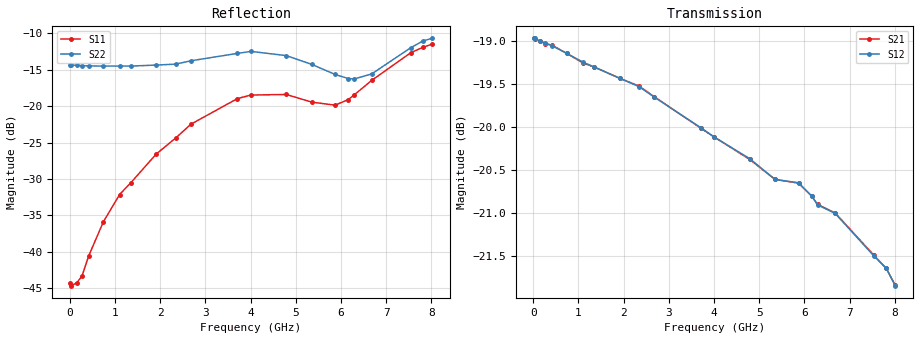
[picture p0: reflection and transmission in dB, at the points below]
! DEVICE ID: PE43712
! File Path: z:\PE43713\PE43713_CHAR_NOM_04292014\AMB\3p300\LS_ATT_17p75dB\PE43713_AMB_3p300V_3p000V_0p000V_LS_ATT_17p75dB_S2P_SN_10_A0139A.s2p
! Serial: 10
! Lot: A0139A
! Temp: 25C
! VDD: 3.300
! VSS: 0.000
! Control_Hi: 3.000
! Control_Lo: 0.000
! Attenuation Step: 17.75dB
! Port 1: RF1
! Port 2: RF2
! ThroughPath:1-2
! IDD: 0.0001466372
! ISS: -8.97e-008
#  Hz  S  RI  R  50
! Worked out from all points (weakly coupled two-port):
!   801 points, 10 MHz to 8.01 GHz, reference 50 ohm
!   highest |S21| = -18.97 dB at 10 MHz (marker M1); lowest = -21.8 dB at 8.01 GHz (marker M2)
!   lowest |S11| = -44.7 dB at 30 MHz (marker M3), VSWR 1.01, Z = 49.4 + j0.135 ohm
!   |S11| at or under -10 dB: start of sweep to end of sweep
!   |S22| runs from -16.3 to -10.7 dB; largest |S21 - S12| = 0.00041
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1e7  -0.00606 0.000573  0.1126 -0.000559  0.1126 -0.000561  -0.1928 0.00128
3e7  -0.00568 0.00137  0.1125 -0.00143  0.1126 -0.00144  -0.1922 0.00318
1.5e8  -0.00484 0.00371  0.112 -0.00668  0.112 -0.00669  -0.1906 0.0122
2.7e8  -0.00414 0.00541  0.1112 -0.0117  0.1113 -0.0118  -0.1889 0.0196
4.2e8  -0.00381 0.00859  0.1101 -0.018  0.11 -0.0181  -0.1869 0.0292
7.4e8  -0.00353 0.0156  0.1061 -0.0304  0.1061 -0.0304  -0.1815 0.0513
1.1e9  -0.00217 0.0246  0.1001 -0.043  0.1002 -0.0431  -0.1731 0.075
1.35e9  0.000192 0.0298  0.0955 -0.0512  0.0955 -0.0512  -0.1661 0.0896
1.91e9  0.0088 0.046  0.0827 -0.0675  0.0827 -0.0675  -0.1441 0.1264
2.34e9  0.018 0.0576  0.0709 -0.0783  0.0709 -0.0782  -0.1234 0.1505
2.68e9  0.0268 0.0703  0.0607 -0.0846  0.0606 -0.0846  -0.1051 0.1762
3.71e9  0.0388 0.106  0.0266 -0.0962  0.0265 -0.0963  -0.068 0.2205
4.01e9  0.04 0.1124  0.0167 -0.0972  0.0167 -0.0972  -0.0633 0.2294
4.79e9  0.0435 0.1123  -0.00788 -0.0954  -0.00789 -0.0955  -0.0398 0.2191
5.35e9  0.0559 0.0909  -0.0238 -0.0901  -0.0238 -0.0901  -0.0171 0.1932
5.87e9  0.0767 0.0667  -0.0384 -0.0844  -0.0383 -0.0845  0.0271 0.163
6.16e9  0.0943 0.0586  -0.0466 -0.0783  -0.0465 -0.0784  0.0595 0.1431
6.29e9  0.1057 0.0556  -0.0489 -0.0757  -0.0488 -0.0757  0.0761 0.1336
6.68e9  0.1412 0.0521  -0.0571 -0.0684  -0.057 -0.0684  0.1252 0.1102
7.54e9  0.2242 0.062  -0.071 -0.0452  -0.0709 -0.0452  0.2293 0.1037
7.81e9  0.2441 0.07  -0.0731 -0.0387  -0.0731 -0.0387  0.2587 0.1086
8.01e9  0.2553 0.0763  -0.0735 -0.0337  -0.0734 -0.0338  0.2718 0.1082
